VERSION 5.7 ;
  NOWIREEXTENSIONATPIN ON ;
  DIVIDERCHAR "/" ;
  BUSBITCHARS "[]" ;
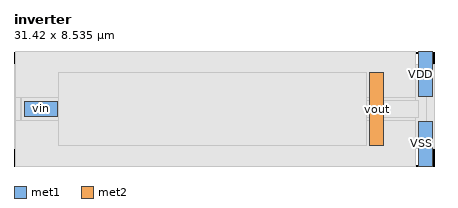
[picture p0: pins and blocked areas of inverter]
MACRO inverter
  CLASS BLOCK ;
  FOREIGN inverter ;
  ORIGIN 0.465 1.465 ;
  SIZE 31.420 BY 8.535 ;
  PIN VDD
    ANTENNADIFFAREA 5.980000 ;
    PORT
      LAYER met1 ;
        RECT 29.820 3.740 30.820 7.070 ;
    END
  END VDD
  PIN VSS
    ANTENNADIFFAREA 6.100000 ;
    PORT
      LAYER met1 ;
        RECT 29.820 -1.465 30.820 1.865 ;
    END
  END VSS
  PIN vin
    ANTENNAGATEAREA 100.000000 ;
    PORT
      LAYER met1 ;
        RECT 0.325 2.250 2.795 3.355 ;
    END
  END vin
  PIN vout
    ANTENNADIFFAREA 10.000000 ;
    PORT
      LAYER met2 ;
        RECT 26.155 0.065 27.210 5.525 ;
    END
  END vout
  OBS
      LAYER nwell ;
        RECT -0.465 -0.130 30.955 6.145 ;
      LAYER li1 ;
        RECT 0.065 0.115 30.410 5.490 ;
      LAYER met1 ;
        RECT -0.345 3.635 29.540 7.070 ;
        RECT -0.345 1.970 0.045 3.635 ;
        RECT 3.075 3.460 29.540 3.635 ;
        RECT 3.075 2.145 29.820 3.460 ;
        RECT 3.075 1.970 29.540 2.145 ;
        RECT -0.345 -1.465 29.540 1.970 ;
      LAYER met2 ;
        RECT 2.890 0.065 25.875 5.525 ;
  END
END inverter
END LIBRARY

